VERSION 5.8 ;
BUSBITCHARS "[]" ;
DIVIDERCHAR "/" ;
UNITS
    DATABASE MICRONS 1000 ;
END UNITS

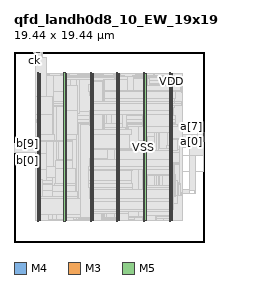
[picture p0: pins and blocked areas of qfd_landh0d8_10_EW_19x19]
MACRO qfd_landh0d8_10_EW_19x19
  FOREIGN qfd_landh0d8_10_EW_19x19 0 0 ;
  CLASS BLOCK ;
  SIZE 19.44 BY 19.44 ;
  PIN a[0]
    DIRECTION INPUT ;
    USE SIGNAL ;
    PORT
      LAYER M4 ;
        RECT  19.356 10.32 19.44 10.344 ;
    END
  END a[0]
  PIN a[1]
    DIRECTION INPUT ;
    USE SIGNAL ;
    PORT
      LAYER M4 ;
        RECT  19.356 10.416 19.44 10.44 ;
    END
  END a[1]
  PIN a[2]
    DIRECTION INPUT ;
    USE SIGNAL ;
    PORT
      LAYER M4 ;
        RECT  19.356 10.512 19.44 10.536 ;
    END
  END a[2]
  PIN a[3]
    DIRECTION INPUT ;
    USE SIGNAL ;
    PORT
      LAYER M4 ;
        RECT  19.356 10.608 19.44 10.632 ;
    END
  END a[3]
  PIN a[4]
    DIRECTION INPUT ;
    USE SIGNAL ;
    PORT
      LAYER M4 ;
        RECT  19.356 10.704 19.44 10.728 ;
    END
  END a[4]
  PIN a[5]
    DIRECTION INPUT ;
    USE SIGNAL ;
    PORT
      LAYER M4 ;
        RECT  19.356 10.8 19.44 10.824 ;
    END
  END a[5]
  PIN a[6]
    DIRECTION INPUT ;
    USE SIGNAL ;
    PORT
      LAYER M4 ;
        RECT  19.356 10.896 19.44 10.92 ;
    END
  END a[6]
  PIN a[7]
    DIRECTION INPUT ;
    USE SIGNAL ;
    PORT
      LAYER M4 ;
        RECT  19.356 10.992 19.44 11.016 ;
    END
  END a[7]
  PIN a[8]
    DIRECTION INPUT ;
    USE SIGNAL ;
    PORT
      LAYER M4 ;
        RECT  19.356 11.088 19.44 11.112 ;
    END
  END a[8]
  PIN a[9]
    DIRECTION INPUT ;
    USE SIGNAL ;
    PORT
      LAYER M4 ;
        RECT  19.356 11.184 19.44 11.208 ;
    END
  END a[9]
  PIN b[0]
    DIRECTION OUTPUT ;
    USE SIGNAL ;
    PORT
      LAYER M4 ;
        RECT  0 9.168 0.084 9.192 ;
    END
  END b[0]
  PIN b[1]
    DIRECTION OUTPUT ;
    USE SIGNAL ;
    PORT
      LAYER M4 ;
        RECT  0 9.264 0.084 9.288 ;
    END
  END b[1]
  PIN b[2]
    DIRECTION OUTPUT ;
    USE SIGNAL ;
    PORT
      LAYER M4 ;
        RECT  0 9.36 0.084 9.384 ;
    END
  END b[2]
  PIN b[3]
    DIRECTION OUTPUT ;
    USE SIGNAL ;
    PORT
      LAYER M4 ;
        RECT  0 9.456 0.084 9.48 ;
    END
  END b[3]
  PIN b[4]
    DIRECTION OUTPUT ;
    USE SIGNAL ;
    PORT
      LAYER M4 ;
        RECT  0 9.552 0.084 9.576 ;
    END
  END b[4]
  PIN b[5]
    DIRECTION OUTPUT ;
    USE SIGNAL ;
    PORT
      LAYER M4 ;
        RECT  0 9.648 0.084 9.672 ;
    END
  END b[5]
  PIN b[6]
    DIRECTION OUTPUT ;
    USE SIGNAL ;
    PORT
      LAYER M4 ;
        RECT  0 9.744 0.084 9.768 ;
    END
  END b[6]
  PIN b[7]
    DIRECTION OUTPUT ;
    USE SIGNAL ;
    PORT
      LAYER M4 ;
        RECT  0 9.84 0.084 9.864 ;
    END
  END b[7]
  PIN b[8]
    DIRECTION OUTPUT ;
    USE SIGNAL ;
    PORT
      LAYER M4 ;
        RECT  0 9.936 0.084 9.96 ;
    END
  END b[8]
  PIN b[9]
    DIRECTION OUTPUT ;
    USE SIGNAL ;
    PORT
      LAYER M4 ;
        RECT  0 10.032 0.084 10.056 ;
    END
  END b[9]
  PIN ck
    DIRECTION INPUT ;
    USE SIGNAL ;
    PORT
      LAYER M3 ;
        RECT  2.124 19.403 2.142 19.44 ;
    END
  END ck
  PIN ck_s
    DIRECTION INPUT ;
    USE SIGNAL ;
    PORT
      LAYER M3 ;
        RECT  2.196 19.403 2.214 19.44 ;
    END
  END ck_s
  PIN en
    DIRECTION INPUT ;
    USE SIGNAL ;
    PORT
      LAYER M3 ;
        RECT  2.268 19.403 2.286 19.44 ;
    END
  END en
  PIN fault
    DIRECTION OUTPUT ;
    USE SIGNAL ;
    PORT
      LAYER M3 ;
        RECT  2.34 19.403 2.358 19.44 ;
    END
  END fault
  PIN k0
    DIRECTION INPUT ;
    USE SIGNAL ;
    PORT
      LAYER M3 ;
        RECT  2.412 19.403 2.43 19.44 ;
    END
  END k0
  PIN k1
    DIRECTION INPUT ;
    USE SIGNAL ;
    PORT
      LAYER M3 ;
        RECT  2.484 19.403 2.502 19.44 ;
    END
  END k1
  PIN k2
    DIRECTION INPUT ;
    USE SIGNAL ;
    PORT
      LAYER M3 ;
        RECT  2.556 19.403 2.574 19.44 ;
    END
  END k2
  PIN k3
    DIRECTION INPUT ;
    USE SIGNAL ;
    PORT
      LAYER M3 ;
        RECT  2.628 19.403 2.646 19.44 ;
    END
  END k3
  PIN rs
    DIRECTION INPUT ;
    USE SIGNAL ;
    PORT
      LAYER M3 ;
        RECT  2.7 19.403 2.718 19.44 ;
    END
  END rs
  PIN tie_hi
    DIRECTION OUTPUT ;
    USE SIGNAL ;
    PORT
      LAYER M3 ;
        RECT  2.772 19.403 2.79 19.44 ;
    END
  END tie_hi
  PIN tie_lo
    DIRECTION OUTPUT ;
    USE SIGNAL ;
    PORT
      LAYER M3 ;
        RECT  2.844 19.403 2.862 19.44 ;
    END
  END tie_lo
  PIN VDD
    DIRECTION INOUT ;
    USE POWER ;
    PORT
      LAYER M5 ;
        RECT  16.092 2.151 16.212 17.289 ;
        RECT  13.392 2.151 13.512 17.289 ;
        RECT  10.692 2.151 10.812 17.289 ;
        RECT  7.992 2.151 8.112 17.289 ;
        RECT  5.292 2.151 5.412 17.289 ;
        RECT  2.592 2.151 2.712 17.289 ;
    END
  END VDD
  PIN VSS
    DIRECTION INOUT ;
    USE GROUND ;
    PORT
      LAYER M5 ;
        RECT  15.9 2.137 16.02 17.303 ;
        RECT  13.2 2.137 13.32 17.303 ;
        RECT  10.5 2.137 10.62 17.303 ;
        RECT  7.8 2.137 7.92 17.303 ;
        RECT  5.1 2.137 5.22 17.303 ;
        RECT  2.4 2.137 2.52 17.303 ;
    END
  END VSS
  OBS
    LAYER RVTN ;
     RECT  2.16 2.16 17.28 2.295 ;
     RECT  2.16 2.565 17.28 2.835 ;
     RECT  2.16 3.105 17.28 3.375 ;
     RECT  2.16 3.645 17.28 3.915 ;
     RECT  2.16 4.185 17.28 4.455 ;
     RECT  2.16 4.725 17.28 4.995 ;
     RECT  2.16 5.265 17.28 5.535 ;
     RECT  2.16 5.805 17.28 6.075 ;
     RECT  2.16 6.345 17.28 6.615 ;
     RECT  2.16 6.885 17.28 7.155 ;
     RECT  2.16 7.425 17.28 7.695 ;
     RECT  2.16 7.965 17.28 8.235 ;
     RECT  2.16 8.505 17.28 8.775 ;
     RECT  2.16 9.045 17.28 9.315 ;
     RECT  2.16 9.585 17.28 9.855 ;
     RECT  2.16 10.125 17.28 10.395 ;
     RECT  2.16 10.665 17.28 10.935 ;
     RECT  2.16 11.205 17.28 11.475 ;
     RECT  2.16 11.745 17.28 12.015 ;
     RECT  2.16 12.285 17.28 12.555 ;
     RECT  2.16 12.825 17.28 13.095 ;
     RECT  2.16 13.365 17.28 13.635 ;
     RECT  2.16 13.905 17.28 14.175 ;
     RECT  2.16 14.445 17.28 14.715 ;
     RECT  2.16 14.985 17.28 15.255 ;
     RECT  2.16 15.525 17.28 15.795 ;
     RECT  2.16 16.065 17.28 16.335 ;
     RECT  2.16 16.605 17.28 16.875 ;
     RECT  2.16 17.145 17.28 17.28 ;
    LAYER RVTP ;
     RECT  2.16 2.295 17.28 2.565 ;
     RECT  2.16 2.835 17.28 3.105 ;
     RECT  2.16 3.375 17.28 3.645 ;
     RECT  2.16 3.915 17.28 4.185 ;
     RECT  2.16 4.455 17.28 4.725 ;
     RECT  2.16 4.995 17.28 5.265 ;
     RECT  2.16 5.535 17.28 5.805 ;
     RECT  2.16 6.075 17.28 6.345 ;
     RECT  2.16 6.615 17.28 6.885 ;
     RECT  2.16 7.155 17.28 7.425 ;
     RECT  2.16 7.695 17.28 7.965 ;
     RECT  2.16 8.235 17.28 8.505 ;
     RECT  2.16 8.775 17.28 9.045 ;
     RECT  2.16 9.315 17.28 9.585 ;
     RECT  2.16 9.855 17.28 10.125 ;
     RECT  2.16 10.395 17.28 10.665 ;
     RECT  2.16 10.935 17.28 11.205 ;
     RECT  2.16 11.475 17.28 11.745 ;
     RECT  2.16 12.015 17.28 12.285 ;
     RECT  2.16 12.555 17.28 12.825 ;
     RECT  2.16 13.095 17.28 13.365 ;
     RECT  2.16 13.635 17.28 13.905 ;
     RECT  2.16 14.175 17.28 14.445 ;
     RECT  2.16 14.715 17.28 14.985 ;
     RECT  2.16 15.255 17.28 15.525 ;
     RECT  2.16 15.795 17.28 16.065 ;
     RECT  2.16 16.335 17.28 16.605 ;
     RECT  2.16 16.875 17.28 17.145 ;
    LAYER M1 ;
     RECT  2.16 2.151 17.28 17.289 ;
    LAYER M2 ;
     RECT  2.047 19.35 2.263 19.368 ;
     RECT  2.263 19.35 2.371 19.404 ;
     RECT  2.371 18.891 2.407 19.404 ;
     RECT  2.407 18.81 2.903 19.404 ;
     RECT  2.903 18.81 3.155 18.828 ;
     RECT  2.16 2.151 17.28 17.289 ;
     RECT  17.28 4.968 17.951 5.328 ;
     RECT  17.951 4.968 18.527 4.986 ;
     RECT  17.28 8.82 18.851 8.838 ;
     RECT  17.28 9.63 18.923 9.648 ;
     RECT  17.28 10.404 18.959 10.998 ;
     RECT  17.28 7.2 19.427 7.218 ;
     RECT  18.959 10.98 19.427 10.998 ;
    LAYER M3 ;
     RECT  5.115 2.143 5.205 2.191 ;
     RECT  7.815 2.143 7.905 2.191 ;
     RECT  9.036 2.155 9.054 2.191 ;
     RECT  15.915 2.143 16.005 2.191 ;
     RECT  2.415 2.143 2.505 2.227 ;
     RECT  7.02 2.191 7.038 2.227 ;
     RECT  7.815 2.191 9.054 2.227 ;
     RECT  12.024 2.191 12.042 2.227 ;
     RECT  13.215 2.143 13.305 2.227 ;
     RECT  2.415 2.227 2.574 2.251 ;
     RECT  3.564 2.191 3.582 2.251 ;
     RECT  4.572 2.191 5.778 2.251 ;
     RECT  12.024 2.227 12.33 2.251 ;
     RECT  13.176 2.227 13.305 2.251 ;
     RECT  14.256 2.191 14.274 2.251 ;
     RECT  10.515 2.143 10.605 2.263 ;
     RECT  6.552 2.227 9.054 2.299 ;
     RECT  6.552 2.299 9.45 2.335 ;
     RECT  10.296 2.263 10.605 2.335 ;
     RECT  14.256 2.251 14.346 2.335 ;
     RECT  14.256 2.335 14.382 2.371 ;
     RECT  15.336 2.191 16.005 2.371 ;
     RECT  6.552 2.335 10.605 2.413 ;
     RECT  13.176 2.251 13.482 2.413 ;
     RECT  14.256 2.371 16.005 2.413 ;
     RECT  11.628 2.251 12.33 2.461 ;
     RECT  13.176 2.413 13.497 2.461 ;
     RECT  2.415 2.251 2.79 2.497 ;
     RECT  3.564 2.251 5.778 2.497 ;
     RECT  2.415 2.497 5.778 2.533 ;
     RECT  6.552 2.413 10.797 2.533 ;
     RECT  11.628 2.461 13.497 2.569 ;
     RECT  11.628 2.569 13.518 2.605 ;
     RECT  14.256 2.413 16.197 2.605 ;
     RECT  2.415 2.533 10.797 2.911 ;
     RECT  11.628 2.605 16.197 2.911 ;
     RECT  2.415 2.911 16.254 3.451 ;
     RECT  2.415 3.451 16.362 3.811 ;
     RECT  2.376 3.811 16.362 3.955 ;
     RECT  2.376 3.955 16.758 4.747 ;
     RECT  2.376 4.747 17.154 5.027 ;
     RECT  18.504 4.963 18.522 5.305 ;
     RECT  2.376 5.027 16.938 5.851 ;
     RECT  2.376 5.851 17.01 5.999 ;
     RECT  2.376 5.999 16.974 8.159 ;
     RECT  17.928 5.305 18.522 8.815 ;
     RECT  19.404 7.195 19.422 8.815 ;
     RECT  2.415 8.159 16.974 9.121 ;
     RECT  0.144 9.403 0.162 9.451 ;
     RECT  0.144 9.451 0.342 9.581 ;
     RECT  2.304 9.121 16.974 10.267 ;
     RECT  17.928 8.815 19.422 10.541 ;
     RECT  2.304 10.267 17.154 10.589 ;
     RECT  18.504 10.541 19.422 10.637 ;
     RECT  2.304 10.589 16.254 10.769 ;
     RECT  2.415 10.769 16.254 10.859 ;
     RECT  18.828 10.637 19.422 11.003 ;
     RECT  18.828 11.003 19.35 11.021 ;
     RECT  18.828 11.021 18.882 11.117 ;
     RECT  18.828 11.117 18.846 11.213 ;
     RECT  11.664 10.859 16.254 11.821 ;
     RECT  11.664 11.821 16.722 11.975 ;
     RECT  2.415 10.859 10.797 12.091 ;
     RECT  11.664 11.975 16.506 12.091 ;
     RECT  2.415 12.091 16.506 12.253 ;
     RECT  2.34 12.253 16.506 12.551 ;
     RECT  2.415 12.551 16.506 12.893 ;
     RECT  2.415 12.893 16.326 13.711 ;
     RECT  2.415 13.711 16.362 13.801 ;
     RECT  2.415 13.801 16.434 13.945 ;
     RECT  2.415 13.945 17.154 14.215 ;
     RECT  2.376 14.215 17.154 14.369 ;
     RECT  17.136 15.331 17.154 15.389 ;
     RECT  2.376 14.369 16.362 15.601 ;
     RECT  17.1 15.457 17.118 15.601 ;
     RECT  2.376 15.601 17.118 16.259 ;
     RECT  2.376 16.259 17.01 16.501 ;
     RECT  2.34 16.501 17.01 16.799 ;
     RECT  12.168 16.799 16.902 16.835 ;
     RECT  12.168 16.835 16.506 16.871 ;
     RECT  2.34 16.799 11.394 16.973 ;
     RECT  12.168 16.871 16.254 16.979 ;
     RECT  12.168 16.979 16.197 17.027 ;
     RECT  2.34 16.973 11.322 17.069 ;
     RECT  12.168 17.027 16.005 17.069 ;
     RECT  4.716 17.069 5.706 17.105 ;
     RECT  6.516 17.069 9.126 17.105 ;
     RECT  10.224 17.069 10.89 17.105 ;
     RECT  12.384 17.069 13.305 17.105 ;
     RECT  14.256 17.069 14.346 17.105 ;
     RECT  2.34 17.069 3.582 17.141 ;
     RECT  5.115 17.105 5.706 17.141 ;
     RECT  7.128 17.105 8.694 17.141 ;
     RECT  10.368 17.105 10.605 17.141 ;
     RECT  12.744 17.105 13.305 17.141 ;
     RECT  7.815 17.141 8.694 17.249 ;
     RECT  5.115 17.141 5.205 17.297 ;
     RECT  7.815 17.249 7.905 17.297 ;
     RECT  10.515 17.141 10.605 17.297 ;
     RECT  13.215 17.141 13.305 17.297 ;
     RECT  15.915 17.069 16.005 17.297 ;
     RECT  2.34 17.141 3.15 18.811 ;
     RECT  2.196 18.811 3.15 18.833 ;
     RECT  2.196 18.833 2.898 19.339 ;
     RECT  2.052 19.339 2.898 19.379 ;
     RECT  2.124 19.379 2.898 19.409 ;
     RECT  2.124 19.409 2.862 19.421 ;
    LAYER M4 ;
     RECT  2.041 19.344 2.185 19.368 ;
     RECT  2.365 5.28 2.408 5.304 ;
     RECT  2.365 7.344 2.408 7.368 ;
     RECT  0.06 9.168 2.408 10.056 ;
     RECT  2.149 13.056 2.408 13.08 ;
     RECT  2.365 15.84 2.408 15.864 ;
     RECT  2.408 2.148 2.512 17.292 ;
     RECT  2.512 2.256 2.704 17.112 ;
     RECT  2.185 18.816 2.819 19.368 ;
     RECT  2.704 6.336 3.299 17.112 ;
     RECT  2.819 18.816 3.299 18.84 ;
     RECT  3.299 7.68 3.34 17.112 ;
     RECT  2.704 2.256 3.973 5.304 ;
     RECT  3.299 6.336 3.973 6.648 ;
     RECT  3.34 7.68 4.061 17.064 ;
     RECT  3.973 2.256 4.309 6.648 ;
     RECT  4.061 7.68 4.309 13.896 ;
     RECT  4.309 2.256 5.029 13.896 ;
     RECT  5.029 2.256 5.108 14.232 ;
     RECT  4.061 15.36 5.108 17.064 ;
     RECT  5.108 2.148 5.212 17.292 ;
     RECT  5.212 2.256 5.404 17.022 ;
     RECT  5.404 2.256 6.422 16.584 ;
     RECT  6.422 2.256 6.581 12.12 ;
     RECT  6.422 13.104 6.653 16.584 ;
     RECT  6.581 2.496 6.833 12.12 ;
     RECT  6.833 2.496 7.808 11.976 ;
     RECT  6.653 13.392 7.808 16.584 ;
     RECT  7.808 2.148 7.912 17.292 ;
     RECT  7.912 2.16 8.104 17.022 ;
     RECT  8.104 2.16 9.065 16.392 ;
     RECT  9.065 2.304 9.205 16.392 ;
     RECT  9.205 2.304 9.281 16.584 ;
     RECT  9.281 2.496 9.461 16.584 ;
     RECT  9.461 2.544 10.316 16.584 ;
     RECT  10.316 2.544 10.508 17.112 ;
     RECT  10.508 2.148 10.612 17.292 ;
     RECT  10.612 2.418 10.804 17.022 ;
     RECT  10.804 2.418 11.513 16.968 ;
     RECT  11.513 2.418 11.612 11.784 ;
     RECT  11.612 2.256 11.699 11.784 ;
     RECT  11.513 13.056 12.197 16.968 ;
     RECT  11.699 2.64 12.697 11.784 ;
     RECT  12.697 2.64 13.208 11.832 ;
     RECT  12.197 13.056 13.208 16.68 ;
     RECT  13.208 2.148 13.312 17.292 ;
     RECT  13.312 2.208 13.504 17.022 ;
     RECT  13.504 12.912 13.817 16.68 ;
     RECT  13.504 2.208 14.329 11.784 ;
     RECT  14.329 2.256 14.531 11.784 ;
     RECT  14.531 2.64 14.773 11.784 ;
     RECT  13.817 12.912 14.773 16.152 ;
     RECT  14.773 2.64 14.861 16.152 ;
     RECT  14.861 2.64 15.685 13.704 ;
     RECT  15.685 2.592 15.908 13.704 ;
     RECT  14.861 14.88 15.908 16.152 ;
     RECT  15.908 2.148 16.012 17.292 ;
     RECT  16.012 2.418 16.204 17.022 ;
     RECT  16.204 9.36 16.265 11.256 ;
     RECT  16.204 12.24 16.265 12.312 ;
     RECT  16.204 3.312 16.355 7.992 ;
     RECT  16.355 4.656 16.373 7.992 ;
     RECT  16.204 14.208 16.453 16.632 ;
     RECT  16.373 4.656 16.481 6.888 ;
     RECT  16.265 12.24 16.481 12.264 ;
     RECT  16.453 14.736 16.547 16.632 ;
     RECT  16.481 4.656 16.553 6.264 ;
     RECT  16.547 15.36 16.625 16.632 ;
     RECT  16.553 4.752 16.733 6.264 ;
     RECT  16.265 9.36 16.733 10.44 ;
     RECT  16.733 4.752 16.805 6.072 ;
     RECT  16.373 7.968 16.841 7.992 ;
     RECT  16.733 9.504 16.913 10.44 ;
     RECT  16.625 15.36 16.913 16.584 ;
     RECT  16.805 4.752 17.021 5.88 ;
     RECT  16.913 16.56 17.075 16.584 ;
     RECT  17.021 4.752 17.165 5.016 ;
     RECT  16.913 10.272 17.165 10.44 ;
     RECT  16.913 15.36 17.165 15.384 ;
     RECT  17.165 10.32 17.917 10.44 ;
     RECT  17.917 10.32 18.493 10.536 ;
     RECT  18.493 10.32 18.817 10.632 ;
     RECT  18.817 10.32 19.404 11.208 ;
    LAYER M5 ;
     RECT  7.8 2.137 7.92 2.149 ;
     RECT  2.4 2.137 2.52 2.151 ;
     RECT  5.1 2.137 5.22 2.151 ;
     RECT  10.5 2.137 10.62 2.151 ;
     RECT  13.2 2.137 13.32 2.151 ;
     RECT  15.9 2.137 16.02 2.151 ;
     RECT  7.8 2.149 8.376 2.197 ;
     RECT  13.2 2.151 13.512 2.197 ;
     RECT  2.4 2.151 2.712 2.245 ;
     RECT  5.1 2.151 5.412 2.245 ;
     RECT  10.5 2.151 10.812 2.245 ;
     RECT  13.2 2.197 14.28 2.245 ;
     RECT  5.1 2.245 6.072 2.533 ;
     RECT  15.9 2.151 16.212 2.581 ;
     RECT  15.696 2.581 16.212 2.629 ;
     RECT  13.2 2.245 14.52 2.677 ;
     RECT  15.6 2.629 16.212 2.677 ;
     RECT  5.1 2.533 6.792 2.773 ;
     RECT  2.4 2.245 3.528 2.821 ;
     RECT  4.992 2.773 6.792 2.821 ;
     RECT  7.8 2.197 8.952 2.869 ;
     RECT  10.5 2.245 11.688 2.869 ;
     RECT  7.8 2.869 11.688 3.109 ;
     RECT  7.8 3.109 11.88 3.157 ;
     RECT  13.2 2.677 16.212 3.157 ;
     RECT  7.8 3.157 16.212 3.301 ;
     RECT  7.8 3.301 16.344 4.163 ;
     RECT  2.4 2.821 6.792 4.403 ;
     RECT  7.8 4.163 16.212 4.501 ;
     RECT  2.4 4.403 6.504 4.691 ;
     RECT  3.984 4.691 6.504 5.171 ;
     RECT  7.68 4.501 16.212 5.363 ;
     RECT  7.68 5.363 12.12 5.605 ;
     RECT  13.104 5.363 16.212 5.605 ;
     RECT  3.984 5.171 6.264 5.747 ;
     RECT  13.104 5.605 16.344 5.747 ;
     RECT  4.176 5.747 6.264 5.987 ;
     RECT  7.584 5.605 12.12 6.035 ;
     RECT  7.584 6.035 12.072 6.323 ;
     RECT  2.4 4.691 2.952 6.371 ;
     RECT  13.104 5.747 13.608 6.853 ;
     RECT  15.216 5.747 16.344 6.853 ;
     RECT  13.104 6.853 16.344 6.899 ;
     RECT  7.632 6.323 12.072 7.333 ;
     RECT  2.4 6.371 2.712 7.381 ;
     RECT  7.632 7.333 12.12 7.381 ;
     RECT  13.104 6.899 16.212 7.381 ;
     RECT  4.272 5.987 6.264 7.571 ;
     RECT  7.632 7.381 16.212 7.715 ;
     RECT  4.272 7.571 6.024 8.387 ;
     RECT  7.68 7.715 16.212 8.435 ;
     RECT  4.32 8.387 6.024 8.483 ;
     RECT  7.68 8.435 9.528 8.579 ;
     RECT  2.4 7.381 3.288 9.013 ;
     RECT  10.5 8.435 16.212 9.347 ;
     RECT  7.8 8.579 9.528 9.493 ;
     RECT  10.5 9.347 13.656 9.493 ;
     RECT  7.8 9.493 13.656 9.539 ;
     RECT  14.736 9.347 16.212 9.587 ;
     RECT  15.648 9.587 16.212 9.923 ;
     RECT  2.4 9.013 3.336 10.309 ;
     RECT  4.512 8.483 6.024 10.309 ;
     RECT  2.4 10.309 6.024 10.355 ;
     RECT  12.864 9.539 13.656 10.355 ;
     RECT  5.1 10.355 6.024 10.453 ;
     RECT  13.2 10.355 13.656 10.837 ;
     RECT  7.8 9.539 11.784 10.981 ;
     RECT  2.4 10.355 4.104 11.027 ;
     RECT  5.1 10.453 6.36 11.029 ;
     RECT  13.2 10.837 14.424 11.221 ;
     RECT  15.9 9.923 16.212 11.221 ;
     RECT  7.8 10.981 12.024 11.507 ;
     RECT  7.8 11.507 11.4 11.555 ;
     RECT  9.264 11.555 11.4 11.699 ;
     RECT  13.2 11.221 16.212 11.797 ;
     RECT  7.8 11.555 8.112 11.941 ;
     RECT  9.264 11.699 11.064 12.083 ;
     RECT  2.4 11.027 3.96 13.045 ;
     RECT  9.984 12.083 11.064 13.045 ;
     RECT  13.104 11.797 16.212 13.045 ;
     RECT  7.68 11.941 8.112 13.093 ;
     RECT  9.984 13.045 16.212 13.093 ;
     RECT  7.68 13.093 16.212 13.427 ;
     RECT  5.1 11.029 6.456 13.429 ;
     RECT  7.8 13.427 16.212 14.197 ;
     RECT  7.8 14.197 16.44 14.387 ;
     RECT  9.216 14.387 16.44 14.725 ;
     RECT  2.16 13.045 3.96 14.867 ;
     RECT  7.8 14.387 8.112 15.013 ;
     RECT  7.68 15.013 8.112 15.349 ;
     RECT  9.216 14.725 16.536 15.349 ;
     RECT  9.216 15.349 17.064 15.539 ;
     RECT  5.1 13.429 6.504 16.019 ;
     RECT  13.2 15.539 17.064 16.019 ;
     RECT  7.632 15.349 8.112 16.115 ;
     RECT  5.1 16.019 5.736 16.595 ;
     RECT  9.216 15.539 11.592 16.595 ;
     RECT  13.2 16.019 13.656 16.595 ;
     RECT  15.9 16.019 17.064 16.595 ;
     RECT  15.9 16.595 16.44 16.643 ;
     RECT  10.368 16.595 11.592 16.979 ;
     RECT  10.368 16.979 10.812 17.123 ;
     RECT  5.1 16.595 5.412 17.289 ;
     RECT  7.8 16.115 8.112 17.289 ;
     RECT  10.5 17.123 10.812 17.289 ;
     RECT  13.2 16.595 13.512 17.289 ;
     RECT  15.9 16.643 16.212 17.289 ;
     RECT  5.1 17.289 5.22 17.303 ;
     RECT  7.8 17.289 7.92 17.303 ;
     RECT  10.5 17.289 10.62 17.303 ;
     RECT  13.2 17.289 13.32 17.303 ;
     RECT  15.9 17.289 16.02 17.303 ;
     RECT  2.16 14.867 3.288 18.851 ;
     RECT  2.16 18.851 2.808 19.379 ;
  END
END qfd_landh0d8_10_EW_19x19
END LIBRARY
